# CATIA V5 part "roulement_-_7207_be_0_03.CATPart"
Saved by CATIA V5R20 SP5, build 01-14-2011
Part number: roulement_-_7207_be_0_03
Bounding box of the stored display mesh (mm): x 2.843 to 14.157, y -32.415 to 32.415, z -32.415 to 32.415
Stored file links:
  C:\DOCUME~1\hermantg\LOCALS~1\Temp\Trace Parts\roulement_-_7207_be_0_03.CATPart

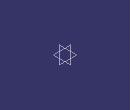
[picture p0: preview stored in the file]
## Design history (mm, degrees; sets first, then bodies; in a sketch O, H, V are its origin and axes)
AxisSystem1: origin (0, 0, 0), X (1, 0, 0), Y (0, 1, 0), Z (0, 0, 1)
Body1 "roulement_-_7207_be_0_03" (main body)
  Solid1: solid without history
